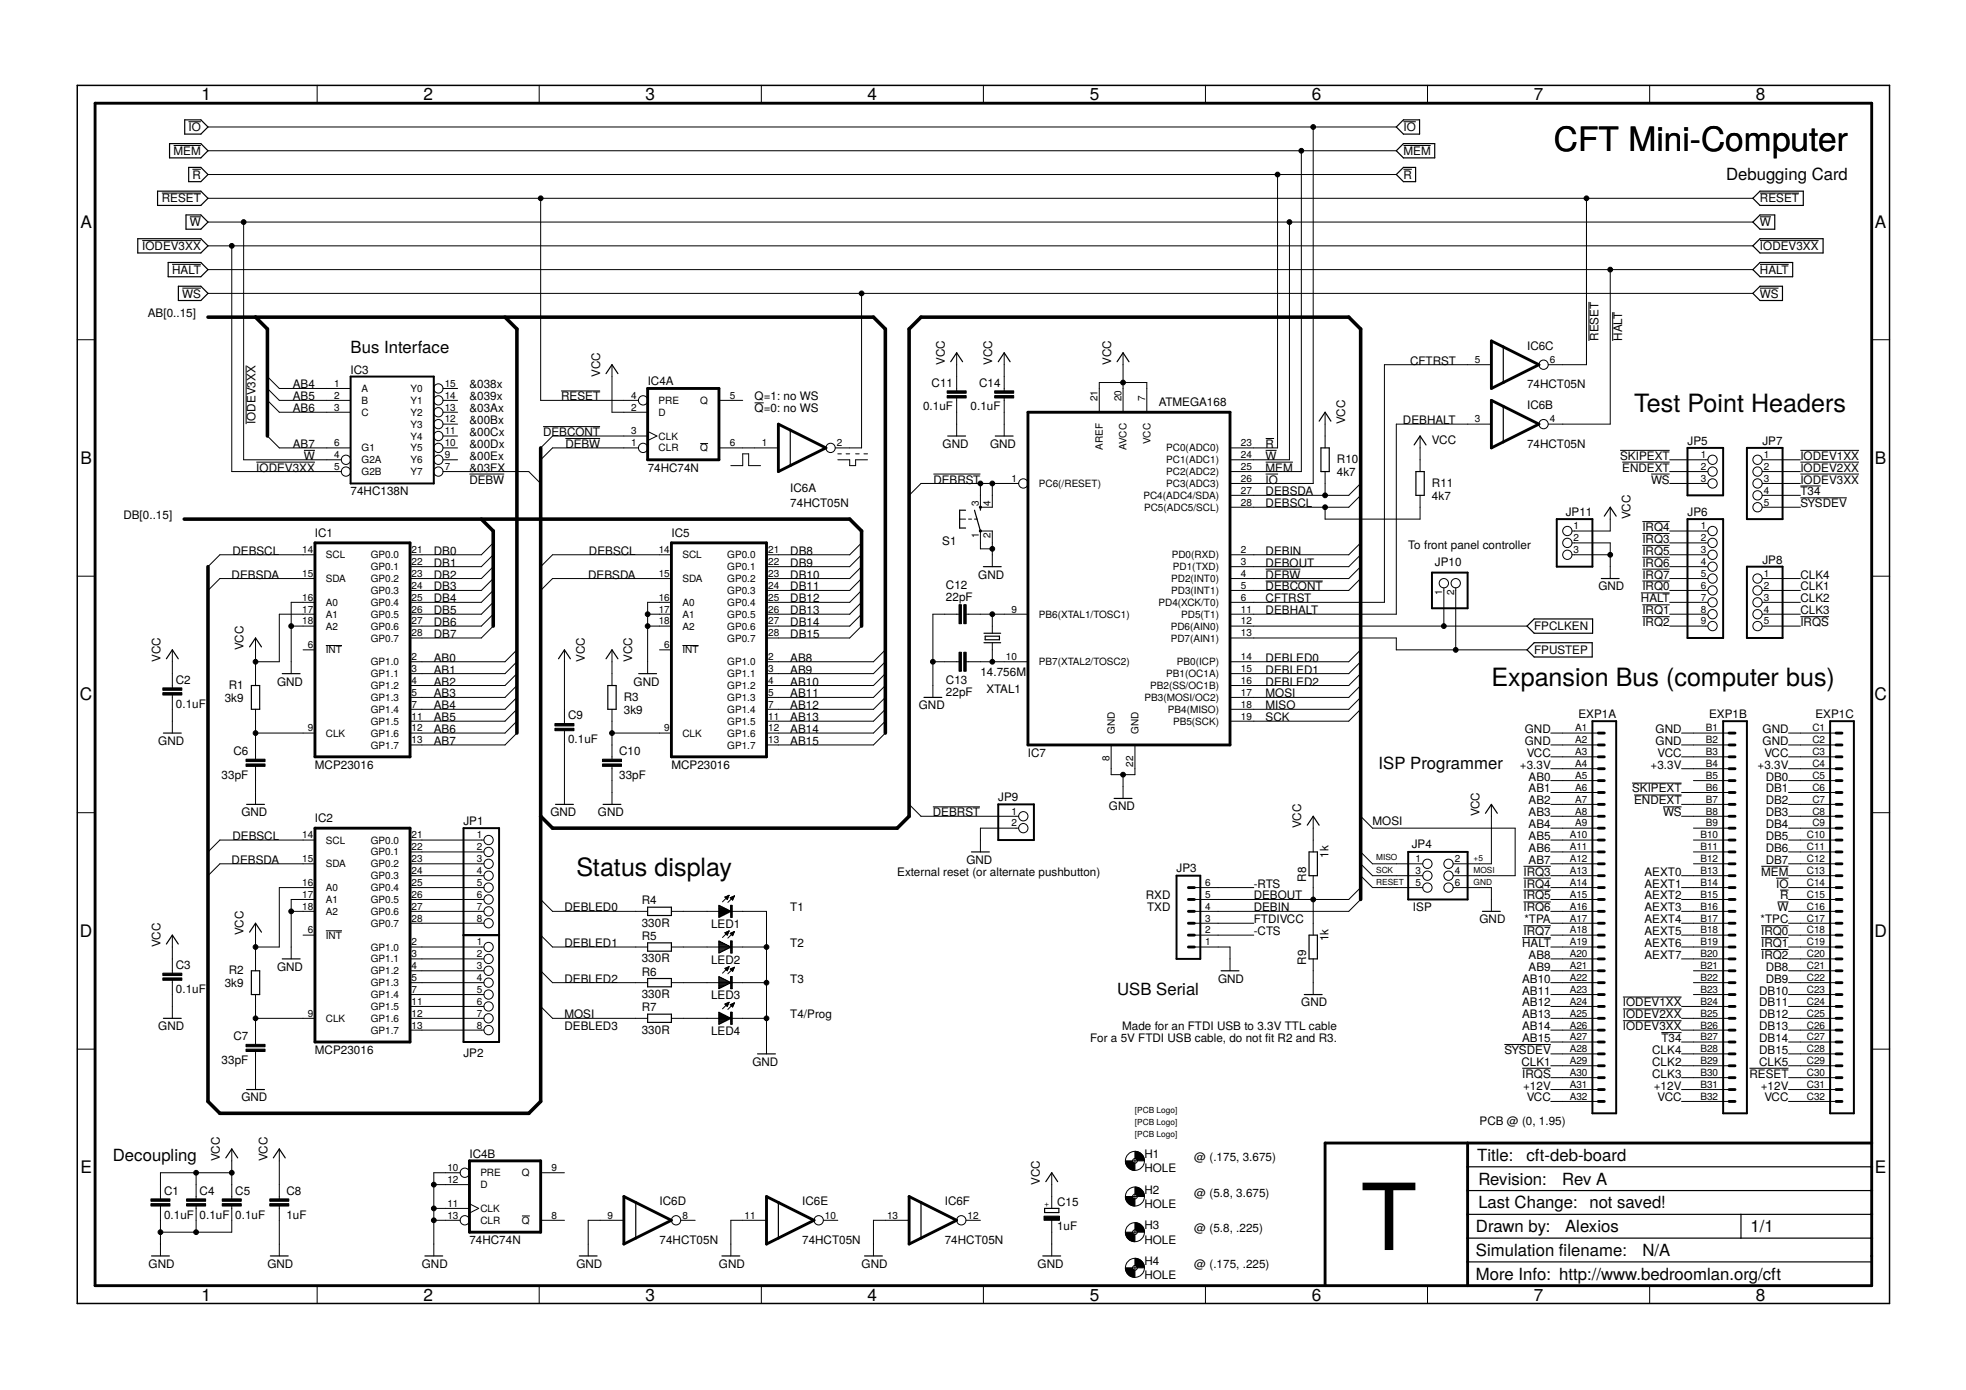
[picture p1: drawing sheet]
<svg xmlns="http://www.w3.org/2000/svg" width="420mm" height="297mm" viewBox="0 0 420 297" stroke-linecap="round" stroke-linejoin="round" font-family="sans-serif">
<defs><g id="words">
<text font-size="19.7" x="290.8" y="267.1">T</text>
<text font-size="7.2" x="332.1" y="32.2">CFT Mini-Computer</text>
<g font-size="5.4">
<text x="349.2" y="88.1">Test Point Headers</text>
<text x="318.7" y="146.5">Expansion Bus (computer bus)</text>
<text x="123.2" y="187.1">Status display</text>
</g>
<g font-size="3.7">
<text x="43" y="21.4">1</text>
<text x="90.5" y="21.4">2</text>
<text x="138" y="21.4">3</text>
<text x="185.4" y="21.4">4</text>
<text x="232.9" y="21.4">5</text>
<text x="280.3" y="21.4">6</text>
<text x="327.8" y="21.4">7</text>
<text x="375.3" y="21.4">8</text>
<text x="17.2" y="48.6">A</text>
<text x="400.7" y="48.6">A</text>
<text x="17.2" y="99.2">B</text>
<text x="400.7" y="99.2">B</text>
<text x="17.1" y="149.7">C</text>
<text x="400.6" y="149.7">C</text>
<text x="17.1" y="200.2">D</text>
<text x="400.6" y="200.2">D</text>
<text x="17.2" y="250.8">E</text>
<text x="400.7" y="250.8">E</text>
<text x="43" y="277.9">1</text>
<text x="90.5" y="277.9">2</text>
<text x="138" y="277.9">3</text>
<text x="185.4" y="277.9">4</text>
<text x="232.9" y="277.9">5</text>
<text x="280.3" y="277.9">6</text>
<text x="327.8" y="277.9">7</text>
<text x="375.3" y="277.9">8</text>
</g>
<g font-size="3.6">
<text x="368.9" y="38.6">Debugging Card</text>
<text x="74.9" y="75.4">Bus Interface</text>
<text x="294.6" y="164.3">ISP Programmer</text>
<text x="238.7" y="212.5">USB Serial</text>
<text x="24.1" y="248.1">Decoupling</text>
<text x="315.7" y="248.1">Title:</text>
<text x="326.2" y="248.2">cft-deb-board</text>
<text x="315.9" y="253.2">Revision:</text>
<text x="333.8" y="253.3">Rev A</text>
<text x="315.4" y="263.3">Drawn by:</text>
<text x="315.9" y="258.2">Last Change: not saved!</text>
<text x="334.5" y="263.3">Alexios</text>
<text x="374.1" y="263.2">1/1</text>
<text x="315.4" y="268.4">Simulation flename:</text>
<text x="333.2" y="268.4">i</text>
<text x="351" y="268.4">N/A</text>
<text x="315.4" y="273.5">More Info: http://www.bedroomlan.org/cft</text>
</g>
<g font-size="2.5">
<text x="40.3" y="28">IO</text>
<text x="299.9" y="28">IO</text>
<text x="37.1" y="33.1">MEM</text>
<text x="299.9" y="33.1">MEM</text>
<text x="41.1" y="38.2">R</text>
<text x="299.9" y="38.2">R</text>
<text x="34.6" y="43.3">RESET</text>
<text x="376.1" y="43.3">RESET</text>
<text x="30.4" y="53.4">IODEV3XX</text>
<text x="40.6" y="48.3">W</text>
<text x="376.1" y="48.3">W</text>
<text x="376.1" y="53.4">IODEV3XX</text>
<text x="36.8" y="58.5">HALT</text>
<text x="376.1" y="58.5">HALT</text>
<text x="39" y="63.6">WS</text>
<text x="376.1" y="63.6">WS</text>
<text x="31.6" y="67.8">AB[0..15]</text>
<text x="201.9" y="77.9" transform="rotate(-90 201.9 77.9)">VCC</text>
<text x="212.1" y="77.9" transform="rotate(-90 212.1 77.9)">VCC</text>
<text x="237.5" y="77.9" transform="rotate(-90 237.5 77.9)">VCC</text>
<text x="301.4" y="77.9">CFTRST</text>
<text x="326.4" y="74.8">IC6C</text>
<text x="341.6" y="72.8" transform="rotate(-90 341.6 72.8)">RESET</text>
<text x="346.7" y="72.8" transform="rotate(-90 346.7 72.8)">HALT</text>
<text x="62.6" y="83">AB4</text>
<text x="74.9" y="79.8">IC3</text>
<text x="100.3" y="83">&amp;038x</text>
<text x="128.3" y="80.5" transform="rotate(-90 128.3 80.5)">VCC</text>
<text x="138.4" y="82.4">IC4A</text>
<text x="199.1" y="82.6">C11</text>
<text x="209.3" y="82.6">C14</text>
<text x="326.4" y="83">74HCT05N</text>
<text x="62.6" y="88.1">AB6</text>
<text x="62.6" y="85.5">AB5</text>
<text x="100.3" y="85.5">&amp;039x</text>
<text x="100.3" y="88.1">&amp;03Ax</text>
<text x="119.9" y="85.5">RESET</text>
<text x="161.3" y="85.5">Q=1: no WS</text>
<text x="161.3" y="88.1">Q=0: no WS</text>
<text x="197.3" y="87.7">0.1uF</text>
<text x="207.4" y="87.7">0.1uF</text>
<text x="247.6" y="86.8">ATMEGA168</text>
<text x="326.4" y="87.5">IC6B</text>
<text x="54.6" y="90.6" transform="rotate(-90 54.6 90.6)">IODEV3XX</text>
<text x="62.6" y="95.7">AB7</text>
<text x="100.3" y="90.6">&amp;00Bx</text>
<text x="100.3" y="93.2">&amp;00Cx</text>
<text x="100.3" y="95.7">&amp;00Dx</text>
<text x="116.1" y="93.2">DEBCONT</text>
<text x="120.8" y="95.7">DEBW</text>
<text x="201.4" y="95.7">GND</text>
<text x="211.6" y="95.7">GND</text>
<text x="270.5" y="95.7">R</text>
<text x="287.5" y="90.6" transform="rotate(-90 287.5 90.6)">VCC</text>
<text x="299.8" y="90.6">DEBHALT</text>
<text x="306" y="94.9">VCC</text>
<text x="326.4" y="95.7">74HCT05N</text>
<text x="360.6" y="95.1">JP5</text>
<text x="376.6" y="95.1">JP7</text>
<text x="54.8" y="100.8">IODEV3XX</text>
<text x="65" y="98.2">W</text>
<text x="100.3" y="98.2">&amp;00Ex</text>
<text x="100.3" y="100.8">&amp;03FX</text>
<text x="138.4" y="100.8">74HC74N</text>
<text x="270.5" y="100.8">MEM</text>
<text x="270.5" y="98.2">W</text>
<text x="285.7" y="101.8">4k7</text>
<text x="285.7" y="99">R10</text>
<text x="346.2" y="98.2">SKIPEXT</text>
<text x="346.7" y="100.8">ENDEXT</text>
<text x="384.8" y="100.8">IODEV2XX</text>
<text x="384.8" y="98.2">IODEV1XX</text>
<text x="74.9" y="105.9">74HC138N</text>
<text x="100.3" y="103.3">DEBW</text>
<text x="168.9" y="105.2">IC6A</text>
<text x="199.5" y="103.3">DEBRST</text>
<text x="270.5" y="103.3">IO</text>
<text x="270.5" y="105.9">DEBSDA</text>
<text x="306" y="106.9">4k7</text>
<text x="306" y="104.1">R11</text>
<text x="352.9" y="103.3">WS</text>
<text x="384.8" y="103.3">IODEV3XX</text>
<text x="384.8" y="105.9">T34</text>
<text x="26.4" y="110.9">DB[0..15]</text>
<text x="168.9" y="108.4">74HCT05N</text>
<text x="270.5" y="108.4">DEBSCL</text>
<text x="334.6" y="110.3">JP11</text>
<text x="348.4" y="110.9" transform="rotate(-90 348.4 110.9)">VCC</text>
<text x="351" y="113.5">IRQ4</text>
<text x="360.6" y="110.3">JP6</text>
<text x="384.8" y="108.4">SYSDEV</text>
<text x="49.7" y="118.6">DEBSCL</text>
<text x="67.3" y="114.8">IC1</text>
<text x="92.7" y="118.6">DB0</text>
<text x="125.9" y="118.6">DEBSCL</text>
<text x="143.5" y="114.8">IC5</text>
<text x="168.9" y="118.6">DB8</text>
<text x="201.4" y="116.5">S1</text>
<text x="270.5" y="118.6">DEBIN</text>
<text x="301" y="117.3">To front panel controller</text>
<text x="351" y="116">IRQ3</text>
<text x="351" y="118.6">IRQ5</text>
<text x="49.5" y="123.6">DEBSDA</text>
<text x="92.7" y="123.6">DB2</text>
<text x="92.7" y="121.1">DB1</text>
<text x="125.7" y="123.6">DEBSDA</text>
<text x="168.9" y="123.6">DB10</text>
<text x="168.9" y="121.1">DB9</text>
<text x="202.2" y="125.8">C12</text>
<text x="209.1" y="123.6">GND</text>
<text x="270.5" y="123.6">DEBW</text>
<text x="270.5" y="121.1">DEBOUT</text>
<text x="306.7" y="121">JP10</text>
<text x="351" y="123.6">IRQ7</text>
<text x="351" y="121.1">IRQ6</text>
<text x="376.6" y="120.5">JP8</text>
<text x="384.8" y="123.6">CLK4</text>
<text x="92.7" y="131.3">DB5</text>
<text x="92.7" y="128.7">DB4</text>
<text x="92.7" y="126.2">DB3</text>
<text x="168.9" y="131.3">DB13</text>
<text x="168.9" y="128.7">DB12</text>
<text x="168.9" y="126.2">DB11</text>
<text x="202.2" y="128.3">22pF</text>
<text x="270.5" y="126.2">DEBCONT</text>
<text x="270.5" y="128.7">CFTRST</text>
<text x="270.5" y="131.3">DEBHALT</text>
<text x="341.6" y="126.2">GND</text>
<text x="350.7" y="128.7">HALT</text>
<text x="351" y="126.2">IRQ0</text>
<text x="351" y="131.3">IRQ1</text>
<text x="384.8" y="128.7">CLK2</text>
<text x="384.8" y="131.3">CLK3</text>
<text x="384.8" y="126.2">CLK1</text>
<text x="92.7" y="136.3">DB7</text>
<text x="92.7" y="133.8">DB6</text>
<text x="168.9" y="136.3">DB15</text>
<text x="168.9" y="133.8">DB14</text>
<text x="327.9" y="134.7">FPCLKEN</text>
<text x="351" y="133.8">IRQ2</text>
<text x="384.8" y="133.8">IRQS</text>
<text x="34.3" y="141.4" transform="rotate(-90 34.3 141.4)">VCC</text>
<text x="52.1" y="138.9" transform="rotate(-90 52.1 138.9)">VCC</text>
<text x="92.7" y="144">AB1</text>
<text x="92.7" y="141.4">AB0</text>
<text x="125" y="141.4" transform="rotate(-90 125 141.4)">VCC</text>
<text x="135.1" y="141.4" transform="rotate(-90 135.1 141.4)">VCC</text>
<text x="168.9" y="144">AB9</text>
<text x="168.9" y="141.4">AB8</text>
<text x="270.5" y="141.4">DEBLED0</text>
<text x="270.5" y="144">DEBLED1</text>
<text x="327.9" y="139.8">FPUSTEP</text>
<text x="37.6" y="146.1">C2</text>
<text x="48.9" y="147.2">R1</text>
<text x="59.2" y="146.5">GND</text>
<text x="92.7" y="149">AB3</text>
<text x="92.7" y="146.5">AB2</text>
<text x="133.3" y="149.8">R3</text>
<text x="135.4" y="146.5">GND</text>
<text x="168.9" y="149">AB11</text>
<text x="168.9" y="146.5">AB10</text>
<text x="202.2" y="148.7">22pF</text>
<text x="202.2" y="146.1">C13</text>
<text x="209.5" y="144.5">14.756M</text>
<text x="210.8" y="148">XTAL1</text>
<text x="270.5" y="149">MOSI</text>
<text x="270.5" y="146.5">DEBLED2</text>
<text x="37.6" y="151.2">0.1uF</text>
<text x="48" y="150.1">3k9</text>
<text x="92.7" y="154.1">AB5</text>
<text x="92.7" y="151.6">AB4</text>
<text x="121.4" y="153.7">C9</text>
<text x="133.3" y="152.6">3k9</text>
<text x="168.9" y="154.1">AB13</text>
<text x="168.9" y="151.6">AB12</text>
<text x="196.4" y="151.6">GND</text>
<text x="270.5" y="151.6">MISO</text>
<text x="270.5" y="154.1">SCK</text>
<text x="337.3" y="153.4">EXP1A</text>
<text x="365.3" y="153.4">EXP1B</text>
<text x="388" y="153.4">EXP1C</text>
<text x="33.8" y="159.2">GND</text>
<text x="49.9" y="161.4">C6</text>
<text x="92.7" y="159.2">AB7</text>
<text x="92.7" y="156.7">AB6</text>
<text x="121.4" y="158.8">0.1uF</text>
<text x="132.3" y="161.4">C10</text>
<text x="168.9" y="159.2">AB15</text>
<text x="168.9" y="156.7">AB14</text>
<text x="219.7" y="161.7">IC7</text>
<text x="325.9" y="159.2">GND</text>
<text x="325.9" y="156.7">GND</text>
<text x="326.3" y="161.7">VCC</text>
<text x="353.8" y="159.2">GND</text>
<text x="353.8" y="156.7">GND</text>
<text x="354.2" y="161.7">VCC</text>
<text x="376.7" y="159.2">GND</text>
<text x="376.7" y="156.7">GND</text>
<text x="377.1" y="161.7">VCC</text>
<text x="47.4" y="166.4">33pF</text>
<text x="67.3" y="164.3">MCP23016</text>
<text x="132.3" y="166.4">33pF</text>
<text x="143.5" y="164.3">MCP23016</text>
<text x="324.8" y="164.3">+3.3V</text>
<text x="326.7" y="166.8">AB0</text>
<text x="352.7" y="164.3">+3.3V</text>
<text x="375.6" y="164.3">+3.3V</text>
<text x="377.4" y="166.8">DB0</text>
<text x="213.3" y="171.3">JP9</text>
<text x="237" y="173.2">GND</text>
<text x="326.7" y="171.9">AB2</text>
<text x="326.7" y="169.4">AB1</text>
<text x="348.8" y="169.4">SKIPEXT</text>
<text x="349.2" y="171.9">ENDEXT</text>
<text x="377.4" y="171.9">DB2</text>
<text x="377.4" y="169.4">DB1</text>
<text x="49.7" y="179.5">DEBSCL</text>
<text x="51.6" y="174.4">GND</text>
<text x="67.3" y="175.7">IC2</text>
<text x="99.1" y="176.3">JP1</text>
<text x="117.6" y="174.4">GND</text>
<text x="127.8" y="174.4">GND</text>
<text x="199.4" y="174.4">DEBRST</text>
<text x="278.1" y="177" transform="rotate(-90 278.1 177)">VCC</text>
<text x="293.3" y="176.2">MOSI</text>
<text x="316.2" y="174.4" transform="rotate(-90 316.2 174.4)">VCC</text>
<text x="326.7" y="179.5">AB5</text>
<text x="326.7" y="177">AB4</text>
<text x="326.7" y="174.4">AB3</text>
<text x="355.4" y="174.4">WS</text>
<text x="377.4" y="179.5">DB5</text>
<text x="377.4" y="177">DB4</text>
<text x="377.4" y="174.4">DB3</text>
<text x="49.5" y="184.6">DEBSDA</text>
<text x="206.5" y="184.6">GND</text>
<text x="283.9" y="183.3" transform="rotate(-90 283.9 183.3)">1k</text>
<text x="301.7" y="181.3">JP4</text>
<text x="326.7" y="184.6">AB7</text>
<text x="326.7" y="182.1">AB6</text>
<text x="377.4" y="184.6">DB7</text>
<text x="377.4" y="182.1">DB6</text>
<text x="191.7" y="187.1">External reset (or alternate pushbutton)</text>
<text x="251.4" y="186.4">JP3</text>
<text x="267.9" y="189.7">-RTS</text>
<text x="279.1" y="188.4" transform="rotate(-90 279.1 188.4)">R8</text>
<text x="325.6" y="187.1">IRQ3</text>
<text x="325.6" y="189.7">IRQ4</text>
<text x="351.4" y="189.7">AEXT1</text>
<text x="351.4" y="187.1">AEXT0</text>
<text x="376.4" y="187.1">MEM</text>
<text x="379.6" y="189.7">IO</text>
<text x="120.6" y="194.7">DEBLED0</text>
<text x="137.1" y="193.2">R4</text>
<text x="168.9" y="194.7">T1</text>
<text x="244.9" y="192.2">RXD</text>
<text x="245.2" y="194.7">TXD</text>
<text x="267.9" y="192.2">DEBOUT</text>
<text x="267.9" y="194.7">DEBIN</text>
<text x="267.9" y="197.3">FTDIVCC</text>
<text x="302" y="194.7">ISP</text>
<text x="316.2" y="197.3">GND</text>
<text x="325.6" y="192.2">IRQ5</text>
<text x="325.6" y="194.7">IRQ6</text>
<text x="325.8" y="197.3">*TPA</text>
<text x="351.4" y="197.3">AEXT4</text>
<text x="351.4" y="194.7">AEXT3</text>
<text x="351.4" y="192.2">AEXT2</text>
<text x="376.3" y="197.3">*TPC</text>
<text x="379.9" y="194.7">W</text>
<text x="380.4" y="192.2">R</text>
<text x="34.3" y="202.4" transform="rotate(-90 34.3 202.4)">VCC</text>
<text x="52.1" y="199.8" transform="rotate(-90 52.1 199.8)">VCC</text>
<text x="120.6" y="202.4">DEBLED1</text>
<text x="137.1" y="198">330R</text>
<text x="137.1" y="200.9">R5</text>
<text x="152" y="198.3">LED1</text>
<text x="168.9" y="202.4">T2</text>
<text x="267.9" y="199.8">-CTS</text>
<text x="283.9" y="201.1" transform="rotate(-90 283.9 201.1)">1k</text>
<text x="325.3" y="202.4">HALT</text>
<text x="325.6" y="199.8">IRQ7</text>
<text x="351.4" y="202.4">AEXT6</text>
<text x="351.4" y="199.8">AEXT5</text>
<text x="376.4" y="199.8">IRQ0</text>
<text x="376.4" y="202.4">IRQ1</text>
<text x="37.6" y="207.1">C3</text>
<text x="48.9" y="208.2">R2</text>
<text x="59.2" y="207.4">GND</text>
<text x="120.6" y="210">DEBLED2</text>
<text x="137.1" y="205.7">330R</text>
<text x="137.1" y="208.5">R6</text>
<text x="152" y="205.9">LED2</text>
<text x="168.9" y="210">T3</text>
<text x="260.3" y="210">GND</text>
<text x="279.1" y="206.2" transform="rotate(-90 279.1 206.2)">R9</text>
<text x="325.3" y="210">AB10</text>
<text x="326.7" y="207.4">AB9</text>
<text x="326.7" y="204.9">AB8</text>
<text x="351.4" y="204.9">AEXT7</text>
<text x="376.4" y="204.9">IRQ2</text>
<text x="377.4" y="210">DB9</text>
<text x="377.4" y="207.4">DB8</text>
<text x="37.6" y="212.1">0.1uF</text>
<text x="48" y="211">3k9</text>
<text x="137.1" y="213.3">330R</text>
<text x="152" y="213.5">LED3</text>
<text x="278.1" y="215.1">GND</text>
<text x="325.3" y="215.1">AB12</text>
<text x="325.3" y="212.5">AB11</text>
<text x="346.8" y="215.1">IODEV1XX</text>
<text x="376" y="215.1">DB11</text>
<text x="376" y="212.5">DB10</text>
<text x="33.8" y="220.1">GND</text>
<text x="120.6" y="217.6">MOSI</text>
<text x="120.6" y="220.1">DEBLED3</text>
<text x="137.1" y="220.9">330R</text>
<text x="137.1" y="216.1">R7</text>
<text x="152" y="221.2">LED4</text>
<text x="168.9" y="217.6">T4/Prog</text>
<text x="239.8" y="220.1">Made for an FTDI USB to 3.3V TTL cable</text>
<text x="325.3" y="220.1">AB14</text>
<text x="325.3" y="217.6">AB13</text>
<text x="346.8" y="220.1">IODEV3XX</text>
<text x="346.8" y="217.6">IODEV2XX</text>
<text x="376" y="220.1">DB13</text>
<text x="376" y="217.6">DB12</text>
<text x="47.4" y="227.4">33pF</text>
<text x="49.9" y="222.3">C7</text>
<text x="67.3" y="225.2">MCP23016</text>
<text x="99.1" y="225.9">JP2</text>
<text x="160.8" y="227.8">GND</text>
<text x="233" y="222.7">For a 5V FTDI USB cable, do not ft R2 and R3.</text>
<text x="270.4" y="222.7">i</text>
<text x="321.5" y="225.2">SYSDEV</text>
<text x="325.2" y="227.8">CLK1</text>
<text x="325.3" y="222.7">AB15</text>
<text x="353.1" y="227.8">CLK2</text>
<text x="353.1" y="225.2">CLK4</text>
<text x="355.1" y="222.7">T34</text>
<text x="376" y="225.2">DB15</text>
<text x="376" y="222.7">DB14</text>
<text x="376" y="227.8">CLK5</text>
<text x="325.3" y="230.3">IRQS</text>
<text x="325.5" y="232.8">+12V</text>
<text x="353.1" y="230.3">CLK3</text>
<text x="353.4" y="232.8">+12V</text>
<text x="373.9" y="230.3">RESET</text>
<text x="376.3" y="232.8">+12V</text>
<text x="51.6" y="235.4">GND</text>
<text x="326.3" y="235.4">VCC</text>
<text x="354.2" y="235.4">VCC</text>
<text x="377.1" y="235.4">VCC</text>
<text x="316.2" y="240.5">PCB @ (0, 1.95)</text>
<text x="47" y="248.1" transform="rotate(-90 47 248.1)">VCC</text>
<text x="57.1" y="248.1" transform="rotate(-90 57.1 248.1)">VCC</text>
<text x="100.3" y="247.4">IC4B</text>
<text x="244.6" y="250.5">HOLE</text>
<text x="244.6" y="247.5">H1</text>
<text x="255.2" y="248.1">@ (.175, 3.675)</text>
<text x="35" y="255.3">C1</text>
<text x="42.7" y="255.3">C4</text>
<text x="50.3" y="255.3">C5</text>
<text x="61.2" y="255.3">C8</text>
<text x="141" y="257.6">IC6D</text>
<text x="171.4" y="257.6">IC6E</text>
<text x="201.9" y="257.6">IC6F</text>
<text x="222.2" y="253.2" transform="rotate(-90 222.2 253.2)">VCC</text>
<text x="225.9" y="257.8">C15</text>
<text x="244.6" y="255.1">H2</text>
<text x="255.2" y="255.7">@ (5.8, 3.675)</text>
<text x="35" y="260.4">0.1uF</text>
<text x="42.7" y="260.4">0.1uF</text>
<text x="50.3" y="260.4">0.1uF</text>
<text x="61.2" y="260.4">1uF</text>
<text x="225.9" y="262.8">1uF</text>
<text x="244.6" y="258.2">HOLE</text>
<text x="244.6" y="262.7">H3</text>
<text x="255.2" y="263.3">@ (5.8, .225)</text>
<text x="100.3" y="265.9">74HC74N</text>
<text x="141" y="265.9">74HCT05N</text>
<text x="171.4" y="265.9">74HCT05N</text>
<text x="201.9" y="265.9">74HCT05N</text>
<text x="244.6" y="265.8">HOLE</text>
<text x="31.7" y="270.9">GND</text>
<text x="57.1" y="270.9">GND</text>
<text x="90.2" y="270.9">GND</text>
<text x="123.2" y="270.9">GND</text>
<text x="153.7" y="270.9">GND</text>
<text x="184.1" y="270.9">GND</text>
<text x="221.8" y="270.9">GND</text>
<text x="244.6" y="273.4">HOLE</text>
<text x="244.6" y="270.4">H4</text>
<text x="255.2" y="270.9">@ (.175, .225)</text>
</g>
<g font-size="2.1">
<text x="315.2" y="77.6">5</text>
<text x="331.2" y="77.6">6</text>
<text x="71.4" y="82.7">1</text>
<text x="77.3" y="83.8">A</text>
<text x="87.8" y="83.8">Y0</text>
<text x="95" y="82.7">15</text>
<text x="71.4" y="85.2">2</text>
<text x="71.4" y="87.7">3</text>
<text x="77.3" y="86.3">B</text>
<text x="77.3" y="88.8">C</text>
<text x="87.8" y="88.8">Y2</text>
<text x="87.8" y="86.3">Y1</text>
<text x="95" y="87.7">13</text>
<text x="95" y="85.2">14</text>
<text x="134.9" y="87.7">2</text>
<text x="134.9" y="85.2">4</text>
<text x="140.8" y="88.8">D</text>
<text x="140.8" y="86.3">PRE</text>
<text x="149.6" y="86.3">Q</text>
<text x="156" y="85.2">5</text>
<text x="234.6" y="85.8" transform="rotate(-90 234.6 85.8)">21</text>
<text x="239.6" y="85.8" transform="rotate(-90 239.6 85.8)">20</text>
<text x="244.7" y="85.8" transform="rotate(-90 244.7 85.8)">7</text>
<text x="71.4" y="95.4">6</text>
<text x="87.8" y="93.9">Y4</text>
<text x="87.8" y="91.4">Y3</text>
<text x="95" y="95.4">10</text>
<text x="95" y="92.8">11</text>
<text x="95" y="90.3">12</text>
<text x="134.9" y="95.4">1</text>
<text x="134.9" y="92.8">3</text>
<text x="140.8" y="93.9">CLK</text>
<text x="156" y="95.4">6</text>
<text x="162.8" y="95.4">1</text>
<text x="178.8" y="95.4">2</text>
<text x="245.8" y="94.8" transform="rotate(-90 245.8 94.8)">VCC</text>
<text x="265.2" y="95.4">23</text>
<text x="315.2" y="90.3">3</text>
<text x="331.2" y="90.3">4</text>
<text x="71.4" y="97.9">4</text>
<text x="71.4" y="100.4">5</text>
<text x="77.3" y="99">G2A</text>
<text x="77.3" y="101.5">G2B</text>
<text x="77.3" y="96.5">G1</text>
<text x="87.8" y="101.5">Y7</text>
<text x="87.8" y="99">Y6</text>
<text x="87.8" y="96.5">Y5</text>
<text x="95" y="100.4">7</text>
<text x="95" y="97.9">9</text>
<text x="140.8" y="96.5">CLR</text>
<text x="149.6" y="96.5">Q</text>
<text x="235.7" y="96.1" transform="rotate(-90 235.7 96.1)">AREF</text>
<text x="240.8" y="96.1" transform="rotate(-90 240.8 96.1)">AVCC</text>
<text x="249.2" y="101.5">PC2(ADC2)</text>
<text x="249.2" y="99">PC1(ADC1)</text>
<text x="249.2" y="96.5">PC0(ADC0)</text>
<text x="265.2" y="100.4">25</text>
<text x="265.2" y="97.9">24</text>
<text x="363.5" y="97.9">1</text>
<text x="363.5" y="100.4">2</text>
<text x="376.9" y="97.9">1</text>
<text x="376.9" y="100.4">2</text>
<text x="216.2" y="103">1</text>
<text x="222" y="104.1">PC6(/RESET)</text>
<text x="244.4" y="106.6">PC4(ADC4/SDA)</text>
<text x="249.2" y="104.1">PC3(ADC3)</text>
<text x="265.2" y="105.5">27</text>
<text x="265.2" y="103">26</text>
<text x="363.5" y="103">3</text>
<text x="376.9" y="103">3</text>
<text x="376.9" y="105.5">4</text>
<text x="209.2" y="108" transform="rotate(-90 209.2 108)">3</text>
<text x="211.7" y="108" transform="rotate(-90 211.7 108)">4</text>
<text x="244.5" y="109.2">PC5(ADC5/SCL)</text>
<text x="265.2" y="108">28</text>
<text x="336.3" y="113.1">1</text>
<text x="363.5" y="113.1">1</text>
<text x="376.9" y="108">5</text>
<text x="64.6" y="118.2">14</text>
<text x="69.6" y="119.3">SCL</text>
<text x="79.2" y="119.3">GP0.0</text>
<text x="88" y="118.2">21</text>
<text x="140.8" y="118.2">14</text>
<text x="145.8" y="119.3">SCL</text>
<text x="155.4" y="119.3">GP0.0</text>
<text x="164.2" y="118.2">21</text>
<text x="209.2" y="115" transform="rotate(-90 209.2 115)">1</text>
<text x="211.7" y="115" transform="rotate(-90 211.7 115)">2</text>
<text x="250.4" y="119.3">PD0(RXD)</text>
<text x="265.2" y="118.2">2</text>
<text x="336.3" y="115.7">2</text>
<text x="336.3" y="118.2">3</text>
<text x="363.5" y="115.7">2</text>
<text x="363.5" y="118.2">3</text>
<text x="64.6" y="123.3">15</text>
<text x="69.6" y="124.4">SDA</text>
<text x="79.2" y="121.9">GP0.1</text>
<text x="79.2" y="124.4">GP0.2</text>
<text x="88" y="120.7">22</text>
<text x="88" y="123.3">23</text>
<text x="88" y="125.8">24</text>
<text x="140.8" y="123.3">15</text>
<text x="145.8" y="124.4">SDA</text>
<text x="155.4" y="121.9">GP0.1</text>
<text x="155.4" y="124.4">GP0.2</text>
<text x="164.2" y="120.7">22</text>
<text x="164.2" y="123.3">23</text>
<text x="164.2" y="125.8">24</text>
<text x="250.3" y="124.4">PD2(INT0)</text>
<text x="250.7" y="121.9">PD1(TXD)</text>
<text x="265.2" y="125.8">5</text>
<text x="265.2" y="123.3">4</text>
<text x="265.2" y="120.7">3</text>
<text x="363.5" y="120.7">4</text>
<text x="363.5" y="123.3">5</text>
<text x="363.5" y="125.8">6</text>
<text x="376.9" y="123.3">1</text>
<text x="376.9" y="125.8">2</text>
<text x="64.6" y="128.4">16</text>
<text x="64.6" y="130.9">17</text>
<text x="69.6" y="129.5">A0</text>
<text x="79.2" y="126.9">GP0.3</text>
<text x="79.2" y="129.5">GP0.4</text>
<text x="88" y="128.4">25</text>
<text x="88" y="130.9">26</text>
<text x="140.8" y="128.4">16</text>
<text x="140.8" y="130.9">17</text>
<text x="145.8" y="129.5">A0</text>
<text x="155.4" y="126.9">GP0.3</text>
<text x="155.4" y="129.5">GP0.4</text>
<text x="164.2" y="128.4">25</text>
<text x="164.2" y="130.9">26</text>
<text x="216.2" y="130.9">9</text>
<text x="247.6" y="129.5">PD4(XCK/T0)</text>
<text x="250.3" y="126.9">PD3(INT1)</text>
<text x="265.2" y="130.9">11</text>
<text x="265.2" y="128.4">6</text>
<text x="308.2" y="127.2" transform="rotate(-90 308.2 127.2)">1</text>
<text x="310.8" y="127.2" transform="rotate(-90 310.8 127.2)">2</text>
<text x="363.5" y="128.4">7</text>
<text x="363.5" y="130.9">8</text>
<text x="376.9" y="128.4">3</text>
<text x="376.9" y="130.9">4</text>
<text x="64.6" y="133.4">18</text>
<text x="69.6" y="132">A1</text>
<text x="69.6" y="134.6">A2</text>
<text x="79.2" y="132">GP0.5</text>
<text x="79.2" y="134.6">GP0.6</text>
<text x="79.2" y="137.1">GP0.7</text>
<text x="88" y="133.4">27</text>
<text x="88" y="136">28</text>
<text x="140.8" y="133.4">18</text>
<text x="145.8" y="132">A1</text>
<text x="145.8" y="134.6">A2</text>
<text x="155.4" y="132">GP0.5</text>
<text x="155.4" y="134.6">GP0.6</text>
<text x="155.4" y="137.1">GP0.7</text>
<text x="164.2" y="133.4">27</text>
<text x="164.2" y="136">28</text>
<text x="222" y="132">PB6(XTAL1/TOSC1)</text>
<text x="250.2" y="137.1">PD7(AIN1)</text>
<text x="250.2" y="134.6">PD6(AIN0)</text>
<text x="252.4" y="132">PD5(T1)</text>
<text x="265.2" y="136">13</text>
<text x="265.2" y="133.4">12</text>
<text x="363.5" y="133.4">9</text>
<text x="376.9" y="133.4">5</text>
<text x="65.8" y="138.5">6</text>
<text x="69.6" y="139.6">INT</text>
<text x="79.2" y="142.2">GP1.0</text>
<text x="88" y="141.1">2</text>
<text x="88" y="143.6">3</text>
<text x="142" y="138.5">6</text>
<text x="145.8" y="139.6">INT</text>
<text x="155.4" y="142.2">GP1.0</text>
<text x="164.2" y="141.1">2</text>
<text x="164.2" y="143.6">3</text>
<text x="215" y="141.1">10</text>
<text x="222" y="142.2">PB7(XTAL2/TOSC2)</text>
<text x="251.5" y="142.2">PB0(ICP)</text>
<text x="265.2" y="143.6">15</text>
<text x="265.2" y="141.1">14</text>
<text x="79.2" y="144.7">GP1.1</text>
<text x="79.2" y="147.3">GP1.2</text>
<text x="79.2" y="149.8">GP1.3</text>
<text x="88" y="146.1">4</text>
<text x="88" y="148.7">5</text>
<text x="155.4" y="144.7">GP1.1</text>
<text x="155.4" y="147.3">GP1.2</text>
<text x="155.4" y="149.8">GP1.3</text>
<text x="164.2" y="146.1">4</text>
<text x="164.2" y="148.7">5</text>
<text x="244.6" y="149.8">PB3(MOSI/OC2)</text>
<text x="245.8" y="147.3">PB2(SS/OC1B)</text>
<text x="249.2" y="144.7">PB1(OC1A)</text>
<text x="265.2" y="148.7">17</text>
<text x="265.2" y="146.1">16</text>
<text x="79.2" y="152.3">GP1.4</text>
<text x="79.2" y="154.9">GP1.5</text>
<text x="88" y="151.2">7</text>
<text x="88" y="153.8">11</text>
<text x="155.4" y="152.3">GP1.4</text>
<text x="155.4" y="154.9">GP1.5</text>
<text x="164.2" y="151.2">7</text>
<text x="164.2" y="153.8">11</text>
<text x="249.6" y="152.3">PB4(MISO)</text>
<text x="250.7" y="154.9">PB5(SCK)</text>
<text x="265.2" y="153.8">19</text>
<text x="265.2" y="151.2">18</text>
<text x="65.8" y="156.3">9</text>
<text x="69.6" y="157.4">CLK</text>
<text x="79.2" y="157.4">GP1.6</text>
<text x="79.2" y="160">GP1.7</text>
<text x="88" y="156.3">12</text>
<text x="88" y="158.8">13</text>
<text x="142" y="156.3">9</text>
<text x="145.8" y="157.4">CLK</text>
<text x="155.4" y="157.4">GP1.6</text>
<text x="155.4" y="160">GP1.7</text>
<text x="164.2" y="156.3">12</text>
<text x="164.2" y="158.8">13</text>
<text x="238.2" y="156.9" transform="rotate(-90 238.2 156.9)">GND</text>
<text x="243.3" y="156.9" transform="rotate(-90 243.3 156.9)">GND</text>
<text x="336.7" y="156.3">A1</text>
<text x="336.7" y="158.8">A2</text>
<text x="336.7" y="161.4">A3</text>
<text x="364.6" y="156.3">B1</text>
<text x="364.6" y="158.8">B2</text>
<text x="364.6" y="161.4">B3</text>
<text x="387.3" y="156.3">C1</text>
<text x="387.3" y="158.8">C2</text>
<text x="387.3" y="161.4">C3</text>
<text x="237.1" y="162.7" transform="rotate(-90 237.1 162.7)">8</text>
<text x="242.2" y="163.9" transform="rotate(-90 242.2 163.9)">22</text>
<text x="336.7" y="163.9">A4</text>
<text x="336.7" y="166.5">A5</text>
<text x="364.6" y="163.9">B4</text>
<text x="364.6" y="166.5">B5</text>
<text x="387.3" y="163.9">C4</text>
<text x="387.3" y="166.5">C5</text>
<text x="336.7" y="169">A6</text>
<text x="336.7" y="171.5">A7</text>
<text x="364.6" y="169">B6</text>
<text x="364.6" y="171.5">B7</text>
<text x="387.3" y="169">C6</text>
<text x="387.3" y="171.5">C7</text>
<text x="64.6" y="179.2">14</text>
<text x="88" y="179.2">21</text>
<text x="101.9" y="179.2">1</text>
<text x="216.2" y="174.1">1</text>
<text x="216.2" y="176.6">2</text>
<text x="335.5" y="179.2">A10</text>
<text x="336.7" y="174.1">A8</text>
<text x="336.7" y="176.6">A9</text>
<text x="363.4" y="179.2">B10</text>
<text x="364.6" y="174.1">B8</text>
<text x="364.6" y="176.6">B9</text>
<text x="386.1" y="179.2">C10</text>
<text x="387.3" y="174.1">C8</text>
<text x="387.3" y="176.6">C9</text>
<text x="64.6" y="184.2">15</text>
<text x="69.6" y="185.4">SDA</text>
<text x="69.6" y="180.3">SCL</text>
<text x="79.2" y="180.3">GP0.0</text>
<text x="79.2" y="182.8">GP0.1</text>
<text x="79.2" y="185.4">GP0.2</text>
<text x="88" y="181.7">22</text>
<text x="88" y="184.2">23</text>
<text x="101.9" y="181.7">2</text>
<text x="101.9" y="184.2">3</text>
<text x="302.5" y="184.2">1</text>
<text x="310.9" y="184.2">2</text>
<text x="335.5" y="181.7">A11</text>
<text x="335.5" y="184.2">A12</text>
<text x="363.4" y="181.7">B11</text>
<text x="363.4" y="184.2">B12</text>
<text x="386.1" y="181.7">C11</text>
<text x="386.1" y="184.2">C12</text>
<text x="64.6" y="189.3">16</text>
<text x="64.6" y="191.9">17</text>
<text x="69.6" y="190.4">A0</text>
<text x="79.2" y="187.9">GP0.3</text>
<text x="79.2" y="190.4">GP0.4</text>
<text x="88" y="186.8">24</text>
<text x="88" y="189.3">25</text>
<text x="88" y="191.9">26</text>
<text x="101.9" y="186.8">4</text>
<text x="101.9" y="189.3">5</text>
<text x="101.9" y="191.9">6</text>
<text x="257.6" y="191.9">5</text>
<text x="257.6" y="189.3">6</text>
<text x="302.5" y="186.8">3</text>
<text x="302.5" y="189.3">5</text>
<text x="310.9" y="186.8">4</text>
<text x="310.9" y="189.3">6</text>
<text x="335.5" y="186.8">A13</text>
<text x="335.5" y="189.3">A14</text>
<text x="335.5" y="191.9">A15</text>
<text x="363.4" y="186.8">B13</text>
<text x="363.4" y="189.3">B14</text>
<text x="363.4" y="191.9">B15</text>
<text x="386.1" y="186.8">C13</text>
<text x="386.1" y="189.3">C14</text>
<text x="386.1" y="191.9">C15</text>
<text x="64.6" y="194.4">18</text>
<text x="69.6" y="193">A1</text>
<text x="69.6" y="195.5">A2</text>
<text x="79.2" y="193">GP0.5</text>
<text x="79.2" y="195.5">GP0.6</text>
<text x="88" y="194.4">27</text>
<text x="88" y="196.9">28</text>
<text x="101.9" y="194.4">7</text>
<text x="101.9" y="196.9">8</text>
<text x="257.6" y="196.9">3</text>
<text x="257.6" y="194.4">4</text>
<text x="335.5" y="194.4">A16</text>
<text x="335.5" y="196.9">A17</text>
<text x="363.4" y="194.4">B16</text>
<text x="363.4" y="196.9">B17</text>
<text x="386.1" y="194.4">C16</text>
<text x="386.1" y="196.9">C17</text>
<text x="65.8" y="199.5">6</text>
<text x="69.6" y="200.6">INT</text>
<text x="79.2" y="203.1">GP1.0</text>
<text x="79.2" y="198">GP0.7</text>
<text x="88" y="202">2</text>
<text x="101.9" y="202">1</text>
<text x="257.6" y="202">1</text>
<text x="257.6" y="199.5">2</text>
<text x="335.5" y="199.5">A18</text>
<text x="335.5" y="202">A19</text>
<text x="363.4" y="199.5">B18</text>
<text x="363.4" y="202">B19</text>
<text x="386.1" y="199.5">C18</text>
<text x="386.1" y="202">C19</text>
<text x="79.2" y="205.7">GP1.1</text>
<text x="79.2" y="208.2">GP1.2</text>
<text x="88" y="204.6">3</text>
<text x="88" y="207.1">4</text>
<text x="88" y="209.6">5</text>
<text x="101.9" y="204.6">2</text>
<text x="101.9" y="207.1">3</text>
<text x="101.9" y="209.6">4</text>
<text x="335.5" y="204.6">A20</text>
<text x="335.5" y="207.1">A21</text>
<text x="335.5" y="209.6">A22</text>
<text x="363.4" y="204.6">B20</text>
<text x="363.4" y="207.1">B21</text>
<text x="363.4" y="209.6">B22</text>
<text x="386.1" y="204.6">C20</text>
<text x="386.1" y="207.1">C21</text>
<text x="386.1" y="209.6">C22</text>
<text x="79.2" y="210.7">GP1.3</text>
<text x="79.2" y="213.3">GP1.4</text>
<text x="79.2" y="215.8">GP1.5</text>
<text x="88" y="212.2">7</text>
<text x="88" y="214.7">11</text>
<text x="101.9" y="212.2">5</text>
<text x="101.9" y="214.7">6</text>
<text x="335.5" y="212.2">A23</text>
<text x="335.5" y="214.7">A24</text>
<text x="363.4" y="212.2">B23</text>
<text x="363.4" y="214.7">B24</text>
<text x="386.1" y="212.2">C23</text>
<text x="386.1" y="214.7">C24</text>
<text x="65.8" y="217.2">9</text>
<text x="69.6" y="218.4">CLK</text>
<text x="79.2" y="218.4">GP1.6</text>
<text x="79.2" y="220.9">GP1.7</text>
<text x="88" y="217.2">12</text>
<text x="88" y="219.8">13</text>
<text x="101.9" y="217.2">7</text>
<text x="101.9" y="219.8">8</text>
<text x="335.5" y="217.2">A25</text>
<text x="335.5" y="219.8">A26</text>
<text x="363.4" y="217.2">B25</text>
<text x="363.4" y="219.8">B26</text>
<text x="386.1" y="217.2">C25</text>
<text x="386.1" y="219.8">C26</text>
<text x="335.5" y="222.3">A27</text>
<text x="335.5" y="224.9">A28</text>
<text x="335.5" y="227.4">A29</text>
<text x="363.4" y="222.3">B27</text>
<text x="363.4" y="224.9">B28</text>
<text x="363.4" y="227.4">B29</text>
<text x="386.1" y="222.3">C27</text>
<text x="386.1" y="224.9">C28</text>
<text x="386.1" y="227.4">C29</text>
<text x="335.5" y="229.9">A30</text>
<text x="335.5" y="232.5">A31</text>
<text x="363.4" y="229.9">B30</text>
<text x="363.4" y="232.5">B31</text>
<text x="386.1" y="229.9">C30</text>
<text x="386.1" y="232.5">C31</text>
<text x="335.5" y="235">A32</text>
<text x="363.4" y="235">B32</text>
<text x="386.1" y="235">C32</text>
<text x="95.6" y="250.3">10</text>
<text x="102.7" y="251.4">PRE</text>
<text x="111.5" y="251.4">Q</text>
<text x="117.9" y="250.3">9</text>
<text x="95.6" y="252.8">12</text>
<text x="95.6" y="257.9">11</text>
<text x="102.7" y="253.9">D</text>
<text x="95.6" y="260.4">13</text>
<text x="102.7" y="261.5">CLR</text>
<text x="102.7" y="259">CLK</text>
<text x="111.5" y="261.5">Q</text>
<text x="117.9" y="260.4">8</text>
<text x="129.8" y="260.4">9</text>
<text x="145.8" y="260.4">8</text>
<text x="159.1" y="260.4">11</text>
<text x="176.3" y="260.4">10</text>
<text x="189.6" y="260.4">13</text>
<text x="206.8" y="260.4">12</text>
</g>
<g font-size="1.8">
<text x="294.1" y="183.8">MISO</text>
<text x="314.9" y="184.1">+5</text>
<text x="294.1" y="189.2">RESET</text>
<text x="294.1" y="186.6">SCK</text>
<text x="314.9" y="186.5">MOSI</text>
<text x="314.9" y="189.2">GND</text>
<text x="242.5" y="237.9">[PCB Logo]</text>
<text x="242.5" y="243">[PCB Logo]</text>
<text x="242.5" y="240.5">[PCB Logo]</text>
<text x="224.2" y="257.8" transform="rotate(-90 224.2 257.8)">+</text>
</g>
</g></defs>
<g fill="none" stroke="#000" stroke-width=".21">
<path d="M67.8 18.2v3.9M115.2 18.2v3.9M162.7 18.2v3.9M210.2 18.2v3.9M257.6 18.2v3.9M305.1 18.2v3.9M352.6 18.2v3.9M20.3 22.1h379.7v252.6h-379.7zM37.1 31.1h5.8M40.3 26h2.6M41.1 36.2h1.8M44.4 32.2h254"/>
<path d="M44.4 27.1h254M44.4 37.3h254M273 37.3v58.4h-10.1M278.1 32.2v68.6h-15.2M280.6 27.1v76.2h-17.7M299.9 31.1h5.9M299.9 26h2.7M299.9 36.2h1.8M30.4 51.4h12.5M34.6 41.3h8.3M36.8 56.5h6.1M40.6 46.3h2.3"/>
<path d="M44.4 47.5h330.2M44.4 57.6h330.2M44.4 42.4h330.2M44.4 52.5h330.2M49.5 52.5v48.3h23.4M52.1 47.5v50.8h20.8M115.5 42.4v43.2h20.9M275.6 47.5v50.8h-12.7M339 42.4v35.5h-8.1M344.1 57.6v33h-13.2M376.1 46.3h2.4M376.1 56.5h6.2"/>
<path d="M376.1 41.3h8.4M376.1 51.4h12.6M16.5 72.6h3.8M39 61.6h3.9M44.4 62.7h330.2M52.6 78.1v12.5M130.8 77.9v10.2h7.6M184.1 62.7v33h-5.6M204.4 75.4v8.1M214.6 75.4v8.1M240 75.4v12.7M318.7 77.9h-22.8v50.8h-33"/>
<path d="M339.6 64.5v8.4M344.7 66.7v6.2M376.1 61.6h4M400 72.6h3.8M54.8 98.8h12.5M57.1 80.5l2.6 2.5h15.2M57.1 83l2.6 2.6h15.2M57.1 85.6l2.6 2.5h15.2M57.1 93.2l2.6 2.5h15.2M65 96.2h2.3M94.7 98.3h3.1M94.7 83h3.1"/>
<path d="M94.7 85.6h3.1M94.7 88.1h3.1M94.7 95.7h3.1M94.7 93.2h3.1M94.7 90.6h3.1M116.1 91.2h12.1M119.9 83.5h8.3M120.8 93.7h7.4M136.4 95.7h-18.3l-2.6 2.6M138.4 93.2h-20.3l-2.6 2.5M138.4 92.2l2 1-2 .9M149.6 94.8h1.7"/>
<path d="M153.6 85.6h5.1M153.6 95.7h12.7M156.2 99.5h2.5v-2.5h1.3v2.5h2.5M161.3 86.1h1.9M179 98.3h2.6v1.2h1.3v-1.2h2.5M179 97h.8M180.8 97h.8M182.9 97h.7M184.6 97h.8M204.4 85v8.2M214.6 85v8.2M234.9 88.1v-6.4h10.2v6.4"/>
<path d="M270.5 98.8h5.8M270.5 93.7h1.8M270.5 96.2h2.3M283.2 88.1v7.6M303.5 93.2v7.6M318.7 90.6h-20.3v40.7h-35.5M346.2 96.2h10.6M346.7 98.8h10.1M356.8 98.3h8.2M376.6 98.3h8.2M384.8 98.8h12.5M384.8 96.2h12.5"/>
<path d="M67.3 118.6h-20.3l-2.6 2.5M94.7 100.8h18.3l2.5 2.5M100.3 101.3h7.5M105.4 116l-2.5 2.6h-15.3M105.4 118.6l-2.5 2.5h-15.3M143.5 118.6h-25.4l-2.6 2.5M184.1 116l-2.5 2.6h-17.8M184.1 118.6l-2.5 2.5h-17.8M199.5 101.3h10M205.1 110.9h1.3M207 110.9h.6M208.3 110.9h.6"/>
<path d="M209.5 103.3v5.1h2.6v-5.1M212.1 117.3h-2.6v-3.8h2.6v7.6M217.7 103.3h-20.9l-2.5 2.6M270.5 101.3h2.6M283.2 100.8v5.1M290.8 116l-2.6 2.6h-25.3M290.8 118.6l-2.6 2.5h-25.3M290.8 105.9l-2.6 2.5h-25.3M290.8 103.3l-2.6 2.6h-25.3M303.5 105.9v5h-20.3v-2.5M336 118.6h8.1M336 116h8.1v7.6"/>
<path d="M344.1 108.4v5.1h-8.1M351 114h5.8M351 111.5h5.8M351 116.5h5.8M351 119.1h5.8M352.9 101.3h3.9M356.8 100.8h8.2M356.8 118.6h8.2M356.8 103.3h8.2M356.8 113.5h8.2M356.8 116h8.2M376.6 100.8h8.2"/>
<path d="M376.6 108.4h8.2M376.6 105.9h8.2M376.6 103.3h8.2M384.8 101.3h12.5M384.8 106.4h9.9M384.8 103.8h4.3M16.5 123.1h3.8M36.8 138.9v8.1M54.6 136.3v10.2M62.2 133.8h5.1M64.8 138.9h2.5M67.3 131.3h-7.6v10.1h-5.1"/>
<path d="M67.3 123.6h-20.3l-2.6 2.6M67.3 128.7h-5.1v15.3M69.6 137.9h3.5M105.4 128.7l-2.5 2.6h-15.3M105.4 121.1l-2.5 2.5h-15.3M105.4 123.6l-2.5 2.6h-15.3M105.4 126.2l-2.5 2.5h-15.3M105.4 131.3l-2.5 2.5h-15.3M105.4 133.8l-2.5 2.5h-15.3M110.5 138.9l-2.6 2.5h-20.3M120.6 138.9v15.7M130.8 138.9v7.6"/>
<path d="M138.4 131.3h5.1M138.4 133.8h5.1M140.9 138.9h2.6M143.5 123.6h-25.4l-2.6 2.6M143.5 128.7h-5.1v15.3M145.8 137.9h3.5M184.1 128.7l-2.5 2.6h-17.8M184.1 121.1l-2.5 2.5h-17.8M184.1 123.6l-2.5 2.6h-17.8M184.1 126.2l-2.5 2.5h-17.8M184.1 131.3l-2.5 2.5h-17.8M184.1 133.8l-2.5 2.5h-17.8"/>
<path d="M189.2 138.9l-2.5 2.5h-22.9M205 131.3h-5.6v17.7M206.5 131.3h13.2M212.1 131.3v4M212.1 137.4v4M262.9 133.8h63.4M262.9 136.3h35.5v2.6h27.9M270.5 124.2h12.2M270.5 121.6h7.4M290.8 138.9l-2.6 2.5h-25.3M290.8 121.1l-2.6 2.5h-25.3M290.8 123.6l-2.6 2.6h-25.3"/>
<path d="M308.6 125.6v8.2M311.1 125.6v13.3M350.7 126.7h6.1M351 124.2h5.8M351 131.8h5.8M351 129.2h5.8M351 121.6h5.8M356.8 131.3h8.2M356.8 123.6h8.2M356.8 121.1h8.2M356.8 126.2h8.2M356.8 128.7h8.2"/>
<path d="M356.8 133.8h8.2M376.6 131.3h8.2M376.6 123.6h8.2M376.6 126.2h8.2M376.6 128.7h8.2M376.6 133.8h8.2M384.8 131.8h6.1M400 123.1h3.8M36.8 148.5v8.2M54.6 156.7h12.7M54.6 151.6v10.6M110.5 154.1l-2.6 2.6h-20.3"/>
<path d="M110.5 156.7l-2.6 2.5h-20.3M110.5 141.4l-2.6 2.6h-20.3M110.5 144l-2.6 2.5h-20.3M110.5 146.5l-2.6 2.5h-20.3M110.5 149l-2.6 2.6h-20.3M110.5 151.6l-2.6 2.5h-20.3M120.6 156.1v15.8M130.8 156.7h12.7M130.8 151.6v10.6M189.2 154.1l-2.5 2.6h-22.9M189.2 156.7l-2.5 2.5h-22.9M189.2 141.4l-2.5 2.6h-22.9"/>
<path d="M189.2 144l-2.5 2.5h-22.9M189.2 146.5l-2.5 2.5h-22.9M189.2 149l-2.5 2.6h-22.9M189.2 151.6l-2.5 2.5h-22.9M199.4 141.4h5.6M206.5 141.4h13.2M237.5 159.2v6.3h5v-6.3M290.8 141.4l-2.6 2.6h-25.3M290.8 144l-2.6 2.5h-25.3M290.8 146.5l-2.6 2.5h-25.3M290.8 149l-2.6 2.6h-25.3M290.8 151.6l-2.6 2.5h-25.3"/>
<path d="M331.4 156.7h10.2M331.4 159.2h10.2M359.4 156.7h10.1M359.4 159.2h10.1M382.2 156.7h10.2M382.2 159.2h10.2M16.5 173.7h3.8M54.6 163.8v8.1M67.3 179.5h-20.3l-2.6 2.6M87.6 179.5h15.8M130.8 163.8v8.1M194.3 171.9l2.5 2.5h20.9"/>
<path d="M199.4 172.4h10M217.7 177h-8.2v5.1M240 165.5v5.1M280.6 174.4v7.7M290.8 174.4l2.5 2.6h30.5v10.1h-13.2M318.7 171.9v12.7h-8.1M331.4 161.7h10.2M331.4 164.3h10.2M331.4 166.8h10.2M331.4 169.4h10.2M331.4 171.9h10.2M331.4 174.4h10.2"/>
<path d="M331.4 177h10.2M331.4 179.5h10.2M348.8 167.3h10.6M349.2 169.9h10.2M355.4 172.4h4M359.4 161.7h10.1M359.4 164.3h10.1M359.4 169.4h10.1M359.4 171.9h10.1M359.4 174.4h10.1M361.9 166.8h7.6M361.9 177h7.6"/>
<path d="M361.9 179.5h7.6M382.2 161.7h10.2M382.2 164.3h10.2M382.2 166.8h10.2M382.2 169.4h10.2M382.2 171.9h10.2M382.2 174.4h10.2M382.2 177h10.2M382.2 179.5h10.2M400 173.7h3.8M36.8 199.8v8.2M54.6 197.3v10.2"/>
<path d="M62.2 194.8h5.1M64.8 199.8h2.5M67.3 184.6h-20.3l-2.6 2.5M67.3 189.7h-7.6v12.7h-5.1M67.3 192.2h-5.1v12.7M69.6 198.9h3.5M87.6 182.1h15.8M87.6 184.6h15.8M87.6 187.1h15.8M87.6 189.7h15.8M87.6 192.2h15.8M87.6 194.8h15.8"/>
<path d="M87.6 197.3h15.8M115.5 192.2l2.6 2.6h20.3M115.5 199.8l2.6 2.6h20.3M143.5 194.8h20.3v30.4M154.9 191.7h.7M154.9 199.3l.9-.4-.4 .9zM155 199.3h.7M155 199.4h.6M155 191.8h.6M155.2 199.5h.4M155.2 191.9h.4M155.2 191.6h.5"/>
<path d="M155.2 199.2h.5M155.3 192.1h.2M155.3 199.7h.2M155.4 199.8h.1M155.4 192.2h.1M155.5 191.5h.2M155.5 199.1h.3M155.8 191.3h.1M155.8 191.3l-1.4 1.4M155.8 191.3l-.9 .4M155.8 191.3l-.4 .9-.5-.5M155.8 198.9l-1.4 1.4"/>
<path d="M155.8 198.9h.1M156.1 199.5l.9-.4-.4 .9zM156.1 191.8h.7M156.1 199.4h.7M156.2 199.5h.6M156.2 191.9h.5M156.3 192.1h.4M156.3 199.7h.4M156.4 191.7h.4M156.4 199.8h.3M156.4 199.3h.4M156.4 192.2h.2"/>
<path d="M156.5 199.9h.1M156.5 192.3h.1M156.6 191.6h.3M156.7 199.2h.2M156.9 191.5h.1M157 191.5l-1.4 1.3M157 191.5l-.9 .3M157 191.5l-.4 .8-.5-.5M157 199.1l-1.4 1.4M255.2 189.7h12.7M255.2 197.3h12.7M255.2 199.8h12.7"/>
<path d="M280.6 187.1v12.7M290.8 182.1l2.5 2.5h10.8M290.8 184.6l2.5 2.5h10.8M290.8 187.1l2.5 2.6h10.8M290.8 189.7l-2.6 2.5h-33M290.8 192.2l-2.6 2.6h-33M310.6 189.7h8.1v5.1M325.6 185.1h5.8M325.6 187.7h5.8M325.6 190.2h5.8M325.6 192.7h5.8M325.6 197.8h5.8"/>
<path d="M331.4 182.1h10.2M331.4 184.6h10.2M331.4 187.1h10.2M331.4 189.7h10.2M331.4 192.2h10.2M331.4 194.8h10.2M331.4 197.3h10.2M331.4 199.8h10.2M359.4 187.1h10.1M359.4 189.7h10.1M359.4 192.2h10.1M359.4 194.8h10.1"/>
<path d="M359.4 197.3h10.1M359.4 199.8h10.1M361.9 182.1h7.6M361.9 184.6h7.6M376.4 197.8h5.8M376.4 185.1h5.8M379.6 187.7h2.6M379.9 192.7h2.3M380.4 190.2h1.8M382.2 182.1h10.2M382.2 184.6h10.2M382.2 187.1h10.2"/>
<path d="M382.2 189.7h10.2M382.2 192.2h10.2M382.2 194.8h10.2M382.2 197.3h10.2M382.2 199.8h10.2M36.8 209.5v8.1M54.6 217.6h12.7M54.6 212.5v10.7M87.6 202.4h15.8M87.6 204.9h15.8M87.6 207.5h15.8M87.6 210h15.8"/>
<path d="M87.6 212.5h15.8M87.6 215.1h15.8M87.6 217.6h15.8M115.5 207.5l2.6 2.5h20.3M115.5 215.1l2.6 2.5h20.3M143.5 202.4h20.3M143.5 210h20.3M143.5 217.6h20.3M154.9 206.9l.9-.3-.4 .9zM154.9 214.6l.9-.4-.4 .9zM155 214.6h.6M155 207h.6"/>
<path d="M155 206.9h.7M155 214.5h.7M155.1 214.7h.5M155.1 207.1h.5M155.2 214.9h.3M155.3 207.3h.2M155.3 206.8h.4M155.3 215h.2M155.3 214.4h.4M155.4 207.4h.1M155.6 206.7h.2M155.6 214.3h.2"/>
<path d="M155.8 206.6l-1.4 1.4M155.8 214.2l-1.4 1.4M156.1 207.1l.9-.4-.4 .9zM156.1 214.7l.9-.4-.4 .9zM156.1 214.7h.7M156.1 207.1h.7M156.2 207h.6M156.2 214.6h.6M156.3 214.9h.4M156.3 207.3h.4M156.4 215h.3M156.4 207.4h.3"/>
<path d="M156.4 206.9h.5M156.5 214.5h.4M156.5 215.1h.1M156.5 207.5h.1M156.7 206.8h.2M156.8 214.4h.1M157 206.7l-1.4 1.4M157 214.3l-1.4 1.4M255.2 202.4h7.7v5.1M280.6 204.9v7.6M325.3 200.4h6.1M331.4 202.4h10.2"/>
<path d="M331.4 204.9h10.2M331.4 207.5h10.2M331.4 210h10.2M331.4 212.5h10.2M331.4 215.1h10.2M331.4 217.6h10.2M346.8 218.1h12.6M346.8 215.6h12.6M346.8 213.1h12.6M359.4 202.4h10.1M359.4 204.9h10.1M359.4 215.1h10.1"/>
<path d="M359.4 217.6h10.1M361.9 207.5h7.6M361.9 210h7.6M361.9 212.5h7.6M376.4 200.4h5.8M376.4 202.9h5.8M382.2 202.4h10.2M382.2 204.9h10.2M382.2 207.5h10.2M382.2 210h10.2M382.2 212.5h10.2M382.2 215.1h10.2"/>
<path d="M382.2 217.6h10.2M16.5 224.2h3.8M54.6 224.7v8.1M87.6 220.1h15.8M321.5 223.2h9.9M325.3 228.3h6.1M331.4 220.1h10.2M331.4 222.7h10.2M331.4 225.2h10.2M331.4 227.8h10.2M331.4 230.3h10.2M331.4 232.8h10.2"/>
<path d="M331.4 235.4h10.2M355 220.7h4.4M359.4 220.1h10.1M359.4 222.7h10.1M359.4 225.2h10.1M359.4 227.8h10.1M359.4 230.3h10.1M359.4 232.8h10.1M359.4 235.4h10.1M373.9 228.3h8.3M382.2 220.1h10.2M382.2 222.7h10.2"/>
<path d="M382.2 225.2h10.2M382.2 227.8h10.2M382.2 230.3h10.2M382.2 232.8h10.2M382.2 235.4h10.2M400 224.2h3.8M34.3 257.7v10.7M41.9 250.6v5.6M41.9 257.7v5.6M49.5 257.7v5.6h-15.2M49.5 250.6h-15.2v5.6M49.5 245.5v10.7"/>
<path d="M59.7 245.5v10.7M59.7 257.7v10.7M92.7 253.2h7.6M92.7 258.2h7.6M98.3 250.6h-5.6v17.8M100.3 257.2l2 1-2 1M111.5 259.8h1.7M115.5 250.6h5.1M224.8 250.6v7.6M242 248.1h1.1M242 255.7h1.1M242.5 247.6v1"/>
<path d="M242.5 255.2v1M67.8 274.7v3.9M92.7 260.8h5.6M115.2 274.7v3.9M115.5 260.8h5.1M133.3 260.8h-7.6v7.6M145.5 260.8h3.1M162.7 274.7v3.9M163.8 260.8h-7.6v7.6M176 260.8h3M194.3 260.8h-7.6v7.6M206.4 260.8h3.1"/>
<path d="M210.2 274.7v3.9M224.8 260.8v7.6M242 263.3h1.1M242 270.9h1.1M242.5 262.8v1M242.5 270.4v1M257.6 274.7v3.9M305.1 274.7v3.9M352.6 274.7v3.9M400 274.6h.1"/>
<circle cx="329.9" cy="77.9" r=".99"/>
<circle cx="73.9" cy="98.3" r=".99"/>
<circle cx="93.7" cy="90.6" r=".99"/>
<circle cx="93.7" cy="93.2" r=".99"/>
<circle cx="93.7" cy="98.3" r=".99"/>
<circle cx="93.7" cy="95.7" r=".99"/>
<circle cx="93.7" cy="88.1" r=".99"/>
<circle cx="93.7" cy="85.6" r=".99"/>
<circle cx="93.7" cy="83" r=".99"/>
<circle cx="137.4" cy="95.7" r=".99"/>
<circle cx="137.4" cy="85.6" r=".99"/>
<circle cx="177.5" cy="95.7" r=".99"/>
<circle cx="329.9" cy="90.6" r=".99"/>
<circle cx="366" cy="98.3" r=".99"/>
<circle cx="375.6" cy="98.3" r=".99"/>
<circle cx="73.9" cy="100.8" r=".99"/>
<circle cx="93.7" cy="100.8" r=".99"/>
<circle cx="218.7" cy="103.3" r=".99"/>
<circle cx="335" cy="116" r=".99"/>
<circle cx="335" cy="113.5" r=".99"/>
<circle cx="335" cy="118.6" r=".99"/>
<circle cx="366" cy="113.5" r=".99"/>
<circle cx="366" cy="100.8" r=".99"/>
<circle cx="366" cy="103.3" r=".99"/>
<circle cx="366" cy="116" r=".99"/>
<circle cx="366" cy="118.6" r=".99"/>
<circle cx="375.6" cy="105.9" r=".99"/>
<circle cx="375.6" cy="103.3" r=".99"/>
<circle cx="375.6" cy="100.8" r=".99"/>
<circle cx="375.6" cy="108.4" r=".99"/>
<circle cx="308.6" cy="124.6" r=".99"/>
<circle cx="311.1" cy="124.6" r=".99"/>
<circle cx="366" cy="126.2" r=".99"/>
<circle cx="366" cy="133.8" r=".99"/>
<circle cx="366" cy="121.1" r=".99"/>
<circle cx="366" cy="128.7" r=".99"/>
<circle cx="366" cy="131.3" r=".99"/>
<circle cx="366" cy="123.6" r=".99"/>
<circle cx="375.6" cy="128.7" r=".99"/>
<circle cx="375.6" cy="133.8" r=".99"/>
<circle cx="375.6" cy="123.6" r=".99"/>
<circle cx="375.6" cy="126.2" r=".99"/>
<circle cx="375.6" cy="131.3" r=".99"/>
<circle cx="104.4" cy="179.5" r=".99"/>
<circle cx="218.7" cy="174.4" r=".99"/>
<circle cx="218.7" cy="177" r=".99"/>
<circle cx="104.4" cy="182.1" r=".99"/>
<circle cx="104.4" cy="187.1" r=".99"/>
<circle cx="104.4" cy="189.7" r=".99"/>
<circle cx="104.4" cy="194.8" r=".99"/>
<circle cx="104.4" cy="197.3" r=".99"/>
<circle cx="104.4" cy="184.6" r=".99"/>
<circle cx="104.4" cy="192.2" r=".99"/>
<circle cx="305.1" cy="187.1" r=".99"/>
<circle cx="305.1" cy="184.6" r=".99"/>
<circle cx="305.1" cy="189.7" r=".99"/>
<circle cx="309.6" cy="187.1" r=".99"/>
<circle cx="309.6" cy="184.6" r=".99"/>
<circle cx="309.6" cy="189.7" r=".99"/>
<circle cx="104.4" cy="207.5" r=".99"/>
<circle cx="104.4" cy="204.9" r=".99"/>
<circle cx="104.4" cy="217.6" r=".99"/>
<circle cx="104.4" cy="202.4" r=".99"/>
<circle cx="104.4" cy="210" r=".99"/>
<circle cx="104.4" cy="212.5" r=".99"/>
<circle cx="104.4" cy="215.1" r=".99"/>
<circle cx="104.4" cy="220.1" r=".99"/>
<circle cx="99.3" cy="250.6" r=".99"/>
<circle cx="242.5" cy="248.1" r="2.03"/>
<circle cx="242.5" cy="255.7" r="2.03"/>
<circle cx="242.5" cy="255.7" r=".51"/>
<circle cx="242.5" cy="248.1" r=".51"/>
<circle cx="99.3" cy="260.8" r=".99"/>
<circle cx="144.5" cy="260.8" r=".99"/>
<circle cx="175" cy="260.8" r=".99"/>
<circle cx="205.4" cy="260.8" r=".99"/>
<circle cx="242.5" cy="270.9" r="2.03"/>
<circle cx="242.5" cy="263.3" r="2.03"/>
<circle cx="242.5" cy="270.9" r=".51"/>
<circle cx="242.5" cy="263.3" r=".51"/>
</g>
<g fill="none" stroke="#000" stroke-width=".25">
<path d="M36.2 30.7h6.7l1.5 1.5-1.5 1.5h-6.7zM39.5 25.6h3.4l1.5 1.5-1.5 1.6h-3.4zM40.3 35.8h2.6l1.5 1.5-1.5 1.5h-2.6zM298.4 27.1l1.5-1.5h3.5v3.1h-3.5zM299.9 30.7h6.7v3h-6.7l-1.5-1.5zM299.9 35.8h2.6v3h-2.6l-1.5-1.5zM29.4 51h13.5l1.5 1.5-1.5 1.6h-13.5zM33.7 40.9h9.2l1.5 1.5-1.5 1.5h-9.2zM35.9 56.1h7l1.5 1.5-1.5 1.5h-7zM39.8 45.9h3.1l1.5 1.6-1.5 1.5h-3.1zM374.6 57.6l1.5-1.5h7v3h-7zM376.1 45.9h3.2v3.1h-3.2l-1.5-1.5z"/>
<path d="M376.1 40.9h9.3v3h-9.3l-1.5-1.5zM376.1 51h13.5v3.1h-13.5l-1.5-1.6zM38.1 61.2h4.8l1.5 1.5-1.5 1.5h-4.8zM129.5 79.8l1.3-1.9 1.3 1.9M203.2 77.3l1.2-1.9 1.3 1.9M213.3 77.3l1.3-1.9 1.3 1.9M238.7 77.3l1.3-1.9 1.3 1.9M321.3 74.1v7.6M374.6 62.7l1.5-1.5h4.8v3h-4.8zM168.9 91.9v7.6M202.5 93.2h3.9M212.7 93.2h3.8"/>
<path d="M281.9 90l1.3-1.9 1.2 1.9M282.3 95.7h1.8v5.1h-1.8zM302.2 95.1l1.3-1.9 1.3 1.9M321.3 86.8v7.6M206.4 109h-1.3v3.8h1.3M208.3 109l1.2 4.5M209.5 108.4v.6M302.6 100.8h1.8v5.1h-1.8zM342.9 110.3l1.2-1.9 1.3 1.9M53.3 138.2l1.3-1.9 1.3 1.9M210.2 121.1h3.8M210.3 135.3h3.5"/>
<path d="M210.3 137.4h3.5M210.5 136h3.1v.7h-3.1zM326.3 133.8l1.6-1.5h12.5v3h-12.5zM326.3 138.9l1.6-1.5h12.4v3h-12.4zM342.2 123.6h3.8M34.9 156.7h3.8M35.6 140.8l1.2-1.9 1.3 1.9M53.7 146.5h1.8v5.1h-1.8zM60.3 144h3.8M119.4 140.8l1.2-1.9 1.3 1.9M129.5 140.8l1.3-1.9 1.3 1.9M129.9 146.5h1.8v5.1h-1.8z"/>
<path d="M136.5 144h3.8M197.5 149h3.8M52.7 171.9h3.8M118.7 171.9h3.8M128.9 171.9h3.8M238.1 170.6h3.8M279.4 176.3l1.2-1.9 1.3 1.9M317.5 173.8l1.2-1.9 1.3 1.9M53.3 199.2l1.3-1.9 1.3 1.9M138.4 193.9h5.1v1.7h-5.1zM153.6 195.7h.7M153.6 193.9h.9"/>
<path d="M153.6 193.5l2.6 1.3-2.6 1.2zM153.6 195.9h.3M153.6 195.5h1.2M153.6 195.2h1.6M153.6 195h2.1M153.6 194.8h2.5M153.6 194.6h2.2M153.6 194.3h1.8M153.6 194.1h1.3M153.6 193.7h.4M156.2 195.7h.2M156.2 193.9h.2"/>
<path d="M156.2 193.5h.2v2.5h-.2zM156.2 195.9h.2M156.2 195.5h.2M156.2 195.2h.2M156.2 195h.2M156.2 194.8h.2M156.2 194.6h.2M156.2 194.3h.2M156.2 194.1h.2M156.2 193.7h.2M207.6 182.1h3.8M279.8 182.1h1.7v5h-1.7z"/>
<path d="M279.8 199.8h1.7v5.1h-1.7zM316.8 194.8h3.8M34.9 217.6h3.8M35.6 201.7l1.2-1.9 1.3 1.9M53.7 207.5h1.8v5h-1.8zM60.3 204.9h3.8M138.4 201.5h5.1v1.8h-5.1zM138.4 209.1h5.1v1.8h-5.1zM138.4 216.7h5.1v1.8h-5.1zM153.6 201.1l2.6 1.3-2.6 1.2zM153.6 208.7l2.6 1.3-2.6 1.3zM153.6 216.3l2.6 1.3-2.6 1.3z"/>
<path d="M153.6 203.5h.4M153.6 203.2h.9M153.6 203h1.3M153.6 202.8h1.8M153.6 202.6h2.2M153.6 202.3h2.5M153.6 202.1h2.1M153.6 201.9h1.6M153.6 201.7h1.2M153.6 201.4h.7M153.6 201.2h.3M153.6 211.2h.1"/>
<path d="M153.6 211h.6M153.6 210.8h1M153.6 210.6h1.4M153.6 210.3h1.9M153.6 210.1h2.3M153.6 209.9h2.4M153.6 209.7h2M153.6 209.4h1.5M153.6 209.2h1.1M153.6 209h.6M153.6 208.8h.2M153.6 218.8h.2"/>
<path d="M153.6 218.6h.7M153.6 218.3h1.1M153.6 218.1h1.6M153.6 217.9h2M153.6 217.7h2.5M153.6 217.4h2.3M153.6 217.2h1.8M153.6 217h1.4M153.6 216.8h.9M153.6 216.6h.5M153.6 216.3h.1M156.2 201.1h.2v2.5h-.2z"/>
<path d="M156.2 208.7h.2v2.6h-.2zM156.2 216.3h.2v2.6h-.2zM156.2 203.5h.2M156.2 203.2h.2M156.2 203h.2M156.2 202.8h.2M156.2 202.6h.2M156.2 202.3h.2M156.2 202.1h.2M156.2 201.9h.2M156.2 201.7h.2M156.2 201.4h.2"/>
<path d="M156.2 201.2h.2M156.2 211.2h.2M156.2 211h.2M156.2 210.8h.2M156.2 210.6h.2M156.2 210.3h.2M156.2 210.1h.2M156.2 209.9h.2M156.2 209.7h.2M156.2 209.4h.2M156.2 209.2h.2M156.2 209h.2"/>
<path d="M156.2 208.8h.2M156.2 218.8h.2M156.2 218.6h.2M156.2 218.3h.2M156.2 218.1h.2M156.2 217.9h.2M156.2 217.7h.2M156.2 217.4h.2M156.2 217.2h.2M156.2 217h.2M156.2 216.8h.2M156.2 216.6h.2"/>
<path d="M261 207.5h3.8M278.7 212.5h3.9M52.7 232.8h3.8M161.9 225.2h3.8M48.3 247.4l1.2-1.9 1.3 1.9M58.4 247.4l1.3-1.9 1.3 1.9M135.9 257v7.6M166.3 257v7.6M196.8 257v7.6M223.2 258.2h3.1v.9h-3.1zM223.5 252.5l1.3-1.9 1.2 1.9M313.6 249.3h86.4"/>
<path d="M313.6 254.4h86.4M313.6 259.5h86.4M372.1 259.5v5.1M32.4 268.4h3.8M57.8 268.4h3.8M90.8 268.4h3.8M123.8 268.4h3.8M154.3 268.4h3.8M184.8 268.4h3.8M222.9 268.4h3.8M313.6 264.6h86.4M400 268.4v1.3h-86.4"/>
</g>
<g fill="none" stroke="#000" stroke-width=".42">
<path d="M74.9 80.5h17.8v22.8h-17.8zM360.6 95.7h7.7v10.2h-7.7zM373.3 95.7h7.7v15.2h-7.7zM332.7 110.9h7.6v10.2h-7.6zM360.6 110.9h7.7v25.4h-7.7zM306 122.4h7.6v7.6h-7.6zM373.3 121.1h7.7v15.2h-7.7zM340.3 154.1h5.1v83.8h-5.1zM368.3 154.1h5v83.8h-5zM391.1 154.1h5.1v83.8h-5.1zM99.1 177h7.6v45.7h-7.6zM213.3 171.9h7.7v7.6h-7.7z"/>
<path d="M99.1 199.8h7.6M251.4 187.1h5.1v17.8h-5.1zM300.9 182.1h12.7v10.1h-12.7z"/>
<circle cx="209.5" cy="108.4" r=".13"/>
<circle cx="209.5" cy="113.5" r=".13"/>
</g>
<g fill="none" stroke="#000" stroke-width=".61">
<path d="M20.3 22.1h379.7v252.6h-379.7zM318.7 72.9l10.2 5-10.2 5.1zM138.4 83h15.2v15.3h-15.2zM166.3 90.6l10.2 5.1-10.2 5.1zM219.7 88.1h43.2v71.1h-43.2zM318.7 85.6l10.2 5-10.2 5.1zM67.3 116h20.3v45.7h-20.3zM143.5 116h20.3v45.7h-20.3zM341.6 159.2h1.3M341.6 156.7h1.3M369.5 159.2h1.3M369.5 156.7h1.3"/>
<path d="M392.4 159.2h1.3M392.4 156.7h1.3M67.3 177h20.3v45.7h-20.3zM341.6 179.5h1.3M341.6 177h1.3M341.6 174.4h1.3M341.6 171.9h1.3M341.6 169.4h1.3M341.6 166.8h1.3M341.6 164.3h1.3M341.6 161.7h1.3M369.5 179.5h1.3"/>
<path d="M369.5 177h1.3M369.5 174.4h1.3M369.5 171.9h1.3M369.5 169.4h1.3M369.5 166.8h1.3M369.5 164.3h1.3M369.5 161.7h1.3M392.4 179.5h1.3M392.4 177h1.3M392.4 174.4h1.3M392.4 171.9h1.3M392.4 169.4h1.3"/>
<path d="M392.4 166.8h1.3M392.4 164.3h1.3M392.4 161.7h1.3M254 199.8h1.2M254 197.3h1.2M254 194.8h1.2M254 192.2h1.2M254 189.7h1.2M341.6 199.8h1.3M341.6 197.3h1.3M341.6 194.8h1.3M341.6 192.2h1.3"/>
<path d="M341.6 189.7h1.3M341.6 187.1h1.3M341.6 184.6h1.3M341.6 182.1h1.3M369.5 199.8h1.3M369.5 197.3h1.3M369.5 194.8h1.3M369.5 192.2h1.3M369.5 189.7h1.3M369.5 187.1h1.3M369.5 184.6h1.3M369.5 182.1h1.3"/>
<path d="M392.4 199.8h1.3M392.4 197.3h1.3M392.4 194.8h1.3M392.4 192.2h1.3M392.4 189.7h1.3M392.4 187.1h1.3M392.4 184.6h1.3M392.4 182.1h1.3M254 202.4h1.2M341.6 217.6h1.3M341.6 215.1h1.3M341.6 212.5h1.3"/>
<path d="M341.6 210h1.3M341.6 207.5h1.3M341.6 204.9h1.3M341.6 202.4h1.3M369.5 217.6h1.3M369.5 215.1h1.3M369.5 212.5h1.3M369.5 210h1.3M369.5 207.5h1.3M369.5 204.9h1.3M369.5 202.4h1.3M392.4 217.6h1.3"/>
<path d="M392.4 215.1h1.3M392.4 212.5h1.3M392.4 210h1.3M392.4 207.5h1.3M392.4 204.9h1.3M392.4 202.4h1.3M341.6 235.4h1.3M341.6 232.8h1.3M341.6 230.3h1.3M341.6 227.8h1.3M341.6 225.2h1.3M341.6 222.7h1.3"/>
<path d="M341.6 220.1h1.3M369.5 235.4h1.3M369.5 232.8h1.3M369.5 230.3h1.3M369.5 227.8h1.3M369.5 225.2h1.3M369.5 222.7h1.3M369.5 220.1h1.3M392.4 235.4h1.3M392.4 232.8h1.3M392.4 230.3h1.3M392.4 227.8h1.3"/>
<path d="M392.4 225.2h1.3M392.4 222.7h1.3M392.4 220.1h1.3M100.3 248.1h15.2v15.2h-15.2zM133.3 255.7l10.2 5.1-10.2 5.1zM163.8 255.7l10.2 5.1-10.2 5.1zM194.3 255.7l10.1 5.1-10.1 5.1zM313.6 244.3v30.4M400 244.3h-116.8v30.4"/>
</g>
<g fill="#000" stroke="#000" stroke-width=".21">
<path d="M240.5 248.1h1.5l.3 .4 .2 .1v1.5a2 2 0 0 1-2-2z" fill-rule="evenodd"/>
<path d="M240.5 255.7h1.5l.1 .3 .4 .2v1.5a2 2 0 0 1-2-2z" fill-rule="evenodd"/>
<path d="M242.5 246a2.04 2.04 0 0 1 2.1 2.1h-1.5l-.1-.3-.5-.2z" fill-rule="evenodd"/>
<path d="M242.5 253.7a2.04 2.04 0 0 1 2.1 2h-1.5l-.1-.3-.5-.2z" fill-rule="evenodd"/>
<path d="M240.5 263.3h1.5l.1 .3 .4 .2v1.5a2 2 0 0 1-2-2z" fill-rule="evenodd"/>
<path d="M240.5 270.9h1.5l.1 .3 .4 .2v1.6a2 2 0 0 1-2-2.1z" fill-rule="evenodd"/>
<path d="M242.5 261.3a2.04 2.04 0 0 1 2.1 2h-1.5l-.1-.3-.5-.2z" fill-rule="evenodd"/>
<path d="M242.5 268.9a2.04 2.04 0 0 1 2.1 2h-1.5l-.1-.3-.5-.2z" fill-rule="evenodd"/>
<circle cx="273" cy="37.3" r=".51"/>
<circle cx="278.1" cy="32.2" r=".51"/>
<circle cx="280.6" cy="27.1" r=".51"/>
<circle cx="49.5" cy="52.5" r=".51"/>
<circle cx="52.1" cy="47.5" r=".51"/>
<circle cx="115.5" cy="42.4" r=".51"/>
<circle cx="275.6" cy="47.5" r=".51"/>
<circle cx="339" cy="42.4" r=".51"/>
<circle cx="344.1" cy="57.6" r=".51"/>
<circle cx="184.1" cy="62.7" r=".51"/>
<circle cx="240" cy="81.7" r=".51"/>
<circle cx="209.5" cy="103.3" r=".51"/>
<circle cx="212.1" cy="117.3" r=".51"/>
<circle cx="212.1" cy="103.3" r=".51"/>
<circle cx="283.2" cy="108.4" r=".51"/>
<circle cx="283.2" cy="105.9" r=".51"/>
<circle cx="344.1" cy="118.6" r=".51"/>
<circle cx="62.2" cy="133.8" r=".51"/>
<circle cx="138.4" cy="131.3" r=".51"/>
<circle cx="138.4" cy="133.8" r=".51"/>
<circle cx="212.1" cy="131.3" r=".51"/>
<circle cx="308.6" cy="133.8" r=".51"/>
<circle cx="311.1" cy="138.9" r=".51"/>
<circle cx="54.6" cy="156.7" r=".51"/>
<circle cx="54.6" cy="141.4" r=".51"/>
<circle cx="130.8" cy="156.7" r=".51"/>
<circle cx="199.4" cy="141.4" r=".51"/>
<circle cx="212.1" cy="141.4" r=".51"/>
<circle cx="240" cy="165.5" r=".51"/>
<circle cx="62.2" cy="194.8" r=".51"/>
<circle cx="280.6" cy="192.2" r=".51"/>
<circle cx="54.6" cy="217.6" r=".51"/>
<circle cx="54.6" cy="202.4" r=".51"/>
<circle cx="163.8" cy="217.6" r=".51"/>
<circle cx="163.8" cy="202.4" r=".51"/>
<circle cx="163.8" cy="210" r=".51"/>
<circle cx="41.9" cy="250.6" r=".51"/>
<circle cx="49.5" cy="250.6" r=".51"/>
<circle cx="92.7" cy="253.2" r=".51"/>
<circle cx="92.7" cy="258.2" r=".51"/>
<circle cx="34.3" cy="263.3" r=".51"/>
<circle cx="41.9" cy="263.3" r=".51"/>
<circle cx="92.7" cy="260.8" r=".51"/>
</g>
<path d="M16.5 18.2h387.3v260.4h-387.3z" fill="none" stroke="#000" stroke-width=".32"/>
<g fill="#000" stroke="#000" stroke-width=".21">
<path d="M202.4 83.5h4.1v.5h-4.1zM202.4 84.5h4.1v.5h-4.1zM212.6 83.5h4v.5h-4zM212.6 84.5h4v.5h-4zM205 129.2h.5v4.1h-.5zM205 139.4h.5v4h-.5zM206 129.2h.5v4.1h-.5zM206 139.4h.5v4h-.5zM34.8 147h4.1v.5h-4.1zM34.8 148h4.1v.5h-4.1zM118.6 154.6h4.1v.5h-4.1zM118.6 155.6h4.1v.5h-4.1z"/>
<path d="M52.6 163.3h4v.5h-4zM52.6 162.2h4v.6h-4zM128.8 163.3h4v.5h-4zM128.8 162.2h4v.6h-4zM34.8 208h4.1v.5h-4.1zM34.8 209h4.1v.5h-4.1zM52.6 224.2h4v.5h-4zM52.6 223.2h4v.5h-4zM32.3 256.2h4v.5h-4zM32.3 257.2h4v.5h-4zM39.9 256.2h4v.5h-4zM39.9 257.2h4v.5h-4z"/>
<path d="M47.5 256.2h4.1v.5h-4.1zM47.5 257.2h4.1v.5h-4.1zM57.7 257.2h4v.5h-4zM57.7 256.2h4v.5h-4zM223.1 259.9h3.3v.9h-3.3z"/>
</g>
<path d="M44.4 67.8h142.3l2.5 2.5v86.4M54.6 67.8l2.5 2.5v22.9M107.9 67.8l2.6 2.5v86.4M115.5 95.7v139.7l-2.5 2.5h-66l-2.6-2.5v-114.3M39.4 110.9h142.2l2.5 2.6v20.3M102.9 110.9l2.5 2.6v20.3M115.5 174.4l2.6 2.6h73.6l2.6-2.6v-104.1l2.5-2.5h91.4l2.6 2.5v121.9" fill="none" stroke="#000" stroke-width=".76"/>
<use href="#words"/>
</svg>
